VERSION 5.7 ;
  NOWIREEXTENSIONATPIN ON ;
  DIVIDERCHAR "/" ;
  BUSBITCHARS "[]" ;
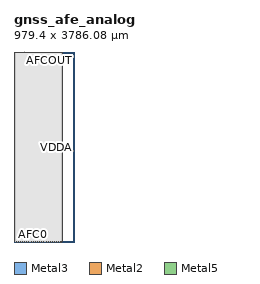
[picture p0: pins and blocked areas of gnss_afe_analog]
MACRO gnss_afe_analog
  CLASS BLOCK ;
  FOREIGN gnss_afe_analog ;
  ORIGIN 0.000 0.000 ;
  SIZE 979.400 BY 3786.080 ;
  PIN VSS
    DIRECTION INOUT ;
    USE GROUND ;
    PORT
      LAYER Metal3 ;
        RECT 6.000 6.000 9.000 3780.080 ;
    END
    PORT
      LAYER Metal2 ;
        RECT 6.500 3779.980 9.390 3786.080 ;
    END
    PORT
      LAYER Metal2 ;
        RECT 10.990 3779.980 21.240 3786.080 ;
    END
    PORT
      LAYER Metal2 ;
        RECT 24.140 3779.980 33.640 3786.080 ;
    END
    PORT
      LAYER Metal2 ;
        RECT 111.360 3779.980 120.860 3786.080 ;
    END
    PORT
      LAYER Metal2 ;
        RECT 123.760 3779.980 134.010 3786.080 ;
    END
    PORT
      LAYER Metal2 ;
        RECT 135.610 3779.980 145.860 3786.080 ;
    END
    PORT
      LAYER Metal2 ;
        RECT 149.140 3779.980 159.390 3786.080 ;
    END
    PORT
      LAYER Metal2 ;
        RECT 160.990 3779.980 171.240 3786.080 ;
    END
    PORT
      LAYER Metal2 ;
        RECT 174.140 3779.980 183.640 3786.080 ;
    END
    PORT
      LAYER Metal2 ;
        RECT 261.360 3779.980 270.860 3786.080 ;
    END
    PORT
      LAYER Metal2 ;
        RECT 273.760 3779.980 284.010 3786.080 ;
    END
    PORT
      LAYER Metal2 ;
        RECT 285.610 3779.980 295.860 3786.080 ;
    END
    PORT
      LAYER Metal2 ;
        RECT 299.140 3779.980 309.390 3786.080 ;
    END
    PORT
      LAYER Metal2 ;
        RECT 310.990 3779.980 321.240 3786.080 ;
    END
    PORT
      LAYER Metal2 ;
        RECT 324.140 3779.980 333.640 3786.080 ;
    END
    PORT
      LAYER Metal2 ;
        RECT 421.360 3779.980 430.860 3786.080 ;
    END
    PORT
      LAYER Metal2 ;
        RECT 433.760 3779.980 444.010 3786.080 ;
    END
    PORT
      LAYER Metal2 ;
        RECT 445.610 3779.980 455.860 3786.080 ;
    END
    PORT
      LAYER Metal2 ;
        RECT 459.140 3779.980 469.390 3786.080 ;
    END
    PORT
      LAYER Metal2 ;
        RECT 470.990 3779.980 481.240 3786.080 ;
    END
    PORT
      LAYER Metal2 ;
        RECT 484.140 3779.980 493.640 3786.080 ;
    END
    PORT
      LAYER Metal5 ;
        RECT 6.000 3777.080 973.400 3780.080 ;
    END
  END VSS
  PIN VDDA
    DIRECTION INOUT ;
    USE POWER ;
    PORT
      LAYER Metal3 ;
        RECT 970.400 6.000 973.400 3780.080 ;
    END
    PORT
      LAYER Metal2 ;
        RECT 36.360 3770.980 45.860 3786.080 ;
    END
    PORT
      LAYER Metal2 ;
        RECT 48.760 3770.980 59.010 3786.080 ;
    END
    PORT
      LAYER Metal2 ;
        RECT 60.610 3770.980 70.860 3786.080 ;
    END
    PORT
      LAYER Metal2 ;
        RECT 74.140 3770.980 84.390 3786.080 ;
    END
    PORT
      LAYER Metal2 ;
        RECT 85.990 3770.980 96.240 3786.080 ;
    END
    PORT
      LAYER Metal2 ;
        RECT 99.140 3770.980 108.640 3786.080 ;
    END
    PORT
      LAYER Metal5 ;
        RECT 6.000 3768.080 45.500 3771.080 ;
    END
    PORT
      LAYER Metal5 ;
        RECT 56.500 3768.080 85.500 3771.080 ;
    END
    PORT
      LAYER Metal5 ;
        RECT 96.500 3768.080 125.500 3771.080 ;
    END
    PORT
      LAYER Metal5 ;
        RECT 136.500 3768.080 165.500 3771.080 ;
    END
    PORT
      LAYER Metal5 ;
        RECT 176.500 3768.080 205.500 3771.080 ;
    END
    PORT
      LAYER Metal5 ;
        RECT 216.500 3768.080 245.500 3771.080 ;
    END
    PORT
      LAYER Metal5 ;
        RECT 256.500 3768.080 285.500 3771.080 ;
    END
    PORT
      LAYER Metal5 ;
        RECT 296.500 3768.080 325.500 3771.080 ;
    END
    PORT
      LAYER Metal5 ;
        RECT 336.500 3768.080 365.500 3771.080 ;
    END
    PORT
      LAYER Metal5 ;
        RECT 376.500 3768.080 405.500 3771.080 ;
    END
    PORT
      LAYER Metal5 ;
        RECT 416.500 3768.080 445.500 3771.080 ;
    END
    PORT
      LAYER Metal5 ;
        RECT 456.500 3768.080 485.500 3771.080 ;
    END
    PORT
      LAYER Metal5 ;
        RECT 496.500 3768.080 525.500 3771.080 ;
    END
    PORT
      LAYER Metal5 ;
        RECT 536.500 3768.080 565.500 3771.080 ;
    END
    PORT
      LAYER Metal5 ;
        RECT 576.500 3768.080 585.500 3771.080 ;
    END
    PORT
      LAYER Metal5 ;
        RECT 596.500 3768.080 605.500 3771.080 ;
    END
    PORT
      LAYER Metal5 ;
        RECT 616.500 3768.080 645.500 3771.080 ;
    END
    PORT
      LAYER Metal5 ;
        RECT 656.500 3768.080 665.500 3771.080 ;
    END
    PORT
      LAYER Metal5 ;
        RECT 676.500 3768.080 685.500 3771.080 ;
    END
    PORT
      LAYER Metal5 ;
        RECT 696.500 3768.080 725.500 3771.080 ;
    END
    PORT
      LAYER Metal5 ;
        RECT 736.500 3768.080 745.500 3771.080 ;
    END
    PORT
      LAYER Metal5 ;
        RECT 756.500 3768.080 765.500 3771.080 ;
    END
    PORT
      LAYER Metal5 ;
        RECT 776.500 3768.080 805.500 3771.080 ;
    END
    PORT
      LAYER Metal5 ;
        RECT 816.500 3768.080 825.500 3771.080 ;
    END
    PORT
      LAYER Metal5 ;
        RECT 836.500 3768.080 845.500 3771.080 ;
    END
    PORT
      LAYER Metal5 ;
        RECT 856.500 3768.080 885.500 3771.080 ;
    END
    PORT
      LAYER Metal5 ;
        RECT 896.500 3768.080 905.500 3771.080 ;
    END
    PORT
      LAYER Metal5 ;
        RECT 916.500 3768.080 925.500 3771.080 ;
    END
    PORT
      LAYER Metal5 ;
        RECT 936.500 3768.080 973.400 3771.080 ;
    END
  END VDDA
  PIN RFIN
    DIRECTION INOUT ;
    USE SIGNAL ;
    ANTENNADIFFAREA 33.599998 ;
    PORT
      LAYER Metal2 ;
        RECT 200.340 3784.040 244.660 3786.080 ;
    END
  END RFIN
  PIN VDDV
    DIRECTION INOUT ;
    USE POWER ;
    PORT
      LAYER Metal2 ;
        RECT 346.360 3775.480 355.860 3786.080 ;
    END
    PORT
      LAYER Metal2 ;
        RECT 358.760 3775.480 369.010 3786.080 ;
    END
    PORT
      LAYER Metal2 ;
        RECT 370.610 3775.480 380.860 3786.080 ;
    END
    PORT
      LAYER Metal2 ;
        RECT 384.140 3775.480 394.390 3786.080 ;
    END
    PORT
      LAYER Metal2 ;
        RECT 395.990 3775.480 406.240 3786.080 ;
    END
    PORT
      LAYER Metal2 ;
        RECT 409.140 3775.480 418.640 3786.080 ;
    END
    PORT
      LAYER Metal5 ;
        RECT 6.000 3772.580 45.500 3775.580 ;
    END
    PORT
      LAYER Metal5 ;
        RECT 56.500 3772.580 85.500 3775.580 ;
    END
    PORT
      LAYER Metal5 ;
        RECT 96.500 3772.580 125.500 3775.580 ;
    END
    PORT
      LAYER Metal5 ;
        RECT 136.500 3772.580 165.500 3775.580 ;
    END
    PORT
      LAYER Metal5 ;
        RECT 176.500 3772.580 205.500 3775.580 ;
    END
    PORT
      LAYER Metal5 ;
        RECT 216.500 3772.580 245.500 3775.580 ;
    END
    PORT
      LAYER Metal5 ;
        RECT 256.500 3772.580 285.500 3775.580 ;
    END
    PORT
      LAYER Metal5 ;
        RECT 296.500 3772.580 325.500 3775.580 ;
    END
    PORT
      LAYER Metal5 ;
        RECT 336.500 3772.580 365.500 3775.580 ;
    END
    PORT
      LAYER Metal5 ;
        RECT 376.500 3772.580 405.500 3775.580 ;
    END
    PORT
      LAYER Metal5 ;
        RECT 416.500 3772.580 445.500 3775.580 ;
    END
    PORT
      LAYER Metal5 ;
        RECT 456.500 3772.580 485.500 3775.580 ;
    END
    PORT
      LAYER Metal5 ;
        RECT 496.500 3772.580 525.500 3775.580 ;
    END
    PORT
      LAYER Metal5 ;
        RECT 536.500 3772.580 565.500 3775.580 ;
    END
    PORT
      LAYER Metal5 ;
        RECT 576.500 3772.580 605.500 3775.580 ;
    END
    PORT
      LAYER Metal5 ;
        RECT 616.500 3772.580 645.500 3775.580 ;
    END
    PORT
      LAYER Metal5 ;
        RECT 656.500 3772.580 685.500 3775.580 ;
    END
    PORT
      LAYER Metal5 ;
        RECT 696.500 3772.580 725.500 3775.580 ;
    END
    PORT
      LAYER Metal5 ;
        RECT 736.500 3772.580 765.500 3775.580 ;
    END
    PORT
      LAYER Metal5 ;
        RECT 776.500 3772.580 805.500 3775.580 ;
    END
    PORT
      LAYER Metal5 ;
        RECT 816.500 3772.580 845.500 3775.580 ;
    END
    PORT
      LAYER Metal5 ;
        RECT 856.500 3772.580 885.500 3775.580 ;
    END
    PORT
      LAYER Metal5 ;
        RECT 896.500 3772.580 925.500 3775.580 ;
    END
    PORT
      LAYER Metal5 ;
        RECT 936.500 3772.580 973.400 3775.580 ;
    END
  END VDDV
  PIN VCTRL
    DIRECTION INOUT ;
    USE SIGNAL ;
    PORT
      LAYER Metal2 ;
        RECT 794.500 3784.040 804.500 3786.080 ;
    END
  END VCTRL
  PIN AFCOUT
    DIRECTION INOUT ;
    USE SIGNAL ;
    PORT
      LAYER Metal2 ;
        RECT 903.500 3784.040 913.500 3786.080 ;
    END
  END AFCOUT
  PIN REFIN
    DIRECTION INOUT ;
    USE SIGNAL ;
    PORT
      LAYER Metal2 ;
        RECT 925.000 3784.040 935.000 3786.080 ;
    END
  END REFIN
  PIN IG1A
    DIRECTION INOUT ;
    USE SIGNAL ;
    ANTENNAGATEAREA 11.200000 ;
    PORT
      LAYER Metal3 ;
        RECT 41.200 -0.100 42.200 0.900 ;
    END
  END IG1A
  PIN IG1B
    DIRECTION INOUT ;
    USE SIGNAL ;
    ANTENNAGATEAREA 22.400000 ;
    PORT
      LAYER Metal3 ;
        RECT 83.900 -0.100 84.900 0.900 ;
    END
  END IG1B
  PIN IG2A
    DIRECTION INOUT ;
    USE SIGNAL ;
    ANTENNAGATEAREA 11.200000 ;
    PORT
      LAYER Metal3 ;
        RECT 126.600 -0.100 127.600 0.900 ;
    END
  END IG2A
  PIN IG2B
    DIRECTION INOUT ;
    USE SIGNAL ;
    ANTENNAGATEAREA 22.400000 ;
    PORT
      LAYER Metal3 ;
        RECT 169.300 -0.100 170.300 0.900 ;
    END
  END IG2B
  PIN IG3A
    DIRECTION INOUT ;
    USE SIGNAL ;
    ANTENNAGATEAREA 11.200000 ;
    PORT
      LAYER Metal3 ;
        RECT 212.000 -0.100 213.000 0.900 ;
    END
  END IG3A
  PIN IG3B
    DIRECTION INOUT ;
    USE SIGNAL ;
    ANTENNAGATEAREA 22.400000 ;
    PORT
      LAYER Metal3 ;
        RECT 254.700 -0.100 255.700 0.900 ;
    END
  END IG3B
  PIN B0
    DIRECTION INOUT ;
    USE SIGNAL ;
    ANTENNAGATEAREA 0.840000 ;
    PORT
      LAYER Metal3 ;
        RECT 297.400 -0.100 298.400 0.900 ;
    END
  END B0
  PIN B1
    DIRECTION INOUT ;
    USE SIGNAL ;
    ANTENNAGATEAREA 0.840000 ;
    PORT
      LAYER Metal3 ;
        RECT 339.400 -0.100 340.400 0.900 ;
    END
  END B1
  PIN AFC0
    DIRECTION INOUT ;
    USE SIGNAL ;
    ANTENNAGATEAREA 0.840000 ;
    PORT
      LAYER Metal3 ;
        RECT 382.100 -0.100 383.100 0.900 ;
    END
  END AFC0
  PIN AFC1
    DIRECTION INOUT ;
    USE SIGNAL ;
    ANTENNAGATEAREA 0.840000 ;
    PORT
      LAYER Metal3 ;
        RECT 424.800 -0.100 425.800 0.900 ;
    END
  END AFC1
  PIN AFC2
    DIRECTION INOUT ;
    USE SIGNAL ;
    ANTENNAGATEAREA 0.840000 ;
    PORT
      LAYER Metal3 ;
        RECT 467.500 -0.100 468.500 0.900 ;
    END
  END AFC2
  PIN AFC3
    DIRECTION INOUT ;
    USE SIGNAL ;
    ANTENNAGATEAREA 0.840000 ;
    PORT
      LAYER Metal3 ;
        RECT 510.200 -0.100 511.200 0.900 ;
    END
  END AFC3
  PIN AFC4
    DIRECTION INOUT ;
    USE SIGNAL ;
    ANTENNAGATEAREA 0.840000 ;
    PORT
      LAYER Metal3 ;
        RECT 552.900 -0.100 553.900 0.900 ;
    END
  END AFC4
  PIN AFC5
    DIRECTION INOUT ;
    USE SIGNAL ;
    ANTENNAGATEAREA 0.840000 ;
    PORT
      LAYER Metal3 ;
        RECT 595.600 -0.100 596.600 0.900 ;
    END
  END AFC5
  PIN AFC6
    DIRECTION INOUT ;
    USE SIGNAL ;
    ANTENNAGATEAREA 0.840000 ;
    PORT
      LAYER Metal3 ;
        RECT 638.300 -0.100 639.300 0.900 ;
    END
  END AFC6
  PIN AFC7
    DIRECTION INOUT ;
    USE SIGNAL ;
    ANTENNAGATEAREA 0.840000 ;
    PORT
      LAYER Metal3 ;
        RECT 680.300 -0.100 681.300 0.900 ;
    END
  END AFC7
  PIN ICP2
    DIRECTION INOUT ;
    USE SIGNAL ;
    ANTENNAGATEAREA 1.960000 ;
    PORT
      LAYER Metal3 ;
        RECT 723.000 -0.100 724.000 0.900 ;
    END
  END ICP2
  PIN I_SIGN
    DIRECTION INOUT ;
    USE SIGNAL ;
    ANTENNAGATEAREA 1.400000 ;
    ANTENNADIFFAREA 2.670000 ;
    PORT
      LAYER Metal3 ;
        RECT 765.700 -0.100 766.700 0.900 ;
    END
  END I_SIGN
  PIN I_MAG
    DIRECTION INOUT ;
    USE SIGNAL ;
    ANTENNADIFFAREA 2.670000 ;
    PORT
      LAYER Metal3 ;
        RECT 808.400 -0.100 809.400 0.900 ;
    END
  END I_MAG
  PIN Q_SIGN
    DIRECTION INOUT ;
    USE SIGNAL ;
    ANTENNAGATEAREA 1.400000 ;
    ANTENNADIFFAREA 2.670000 ;
    PORT
      LAYER Metal3 ;
        RECT 851.100 -0.100 852.100 0.900 ;
    END
  END Q_SIGN
  PIN Q_MAG
    DIRECTION INOUT ;
    USE SIGNAL ;
    ANTENNADIFFAREA 2.670000 ;
    PORT
      LAYER Metal3 ;
        RECT 893.800 -0.100 894.800 0.900 ;
    END
  END Q_MAG
  PIN CLKOUT
    DIRECTION INOUT ;
    USE SIGNAL ;
    ANTENNADIFFAREA 4.770000 ;
    PORT
      LAYER Metal3 ;
        RECT 936.500 -0.100 937.500 0.900 ;
    END
  END CLKOUT
  OBS
      LAYER Nwell ;
        RECT 33.760 16.260 946.360 3761.380 ;
      LAYER Metal1 ;
        RECT 33.945 16.445 946.175 3761.195 ;
      LAYER Metal2 ;
        RECT 9.690 3779.680 10.690 3784.090 ;
        RECT 21.540 3779.680 23.840 3784.090 ;
        RECT 33.940 3779.680 36.060 3784.090 ;
        RECT 6.500 3770.680 36.060 3779.680 ;
        RECT 46.160 3770.680 48.460 3784.090 ;
        RECT 59.310 3770.680 60.310 3784.090 ;
        RECT 71.160 3770.680 73.840 3784.090 ;
        RECT 84.690 3770.680 85.690 3784.090 ;
        RECT 96.540 3770.680 98.840 3784.090 ;
        RECT 108.940 3779.680 111.060 3784.090 ;
        RECT 121.160 3779.680 123.460 3784.090 ;
        RECT 134.310 3779.680 135.310 3784.090 ;
        RECT 146.160 3779.680 148.840 3784.090 ;
        RECT 159.690 3779.680 160.690 3784.090 ;
        RECT 171.540 3779.680 173.840 3784.090 ;
        RECT 183.940 3783.740 200.040 3784.090 ;
        RECT 244.960 3783.740 261.060 3784.090 ;
        RECT 183.940 3779.680 261.060 3783.740 ;
        RECT 271.160 3779.680 273.460 3784.090 ;
        RECT 284.310 3779.680 285.310 3784.090 ;
        RECT 296.160 3779.680 298.840 3784.090 ;
        RECT 309.690 3779.680 310.690 3784.090 ;
        RECT 321.540 3779.680 323.840 3784.090 ;
        RECT 333.940 3779.680 346.060 3784.090 ;
        RECT 108.940 3775.180 346.060 3779.680 ;
        RECT 356.160 3775.180 358.460 3784.090 ;
        RECT 369.310 3775.180 370.310 3784.090 ;
        RECT 381.160 3775.180 383.840 3784.090 ;
        RECT 394.690 3775.180 395.690 3784.090 ;
        RECT 406.540 3775.180 408.840 3784.090 ;
        RECT 418.940 3779.680 421.060 3784.090 ;
        RECT 431.160 3779.680 433.460 3784.090 ;
        RECT 444.310 3779.680 445.310 3784.090 ;
        RECT 456.160 3779.680 458.840 3784.090 ;
        RECT 469.690 3779.680 470.690 3784.090 ;
        RECT 481.540 3779.680 483.840 3784.090 ;
        RECT 493.940 3783.740 794.200 3784.090 ;
        RECT 804.800 3783.740 903.200 3784.090 ;
        RECT 913.800 3783.740 924.700 3784.090 ;
        RECT 935.300 3783.740 956.790 3784.090 ;
        RECT 493.940 3779.680 956.790 3783.740 ;
        RECT 418.940 3775.180 956.790 3779.680 ;
        RECT 108.940 3770.680 956.790 3775.180 ;
        RECT 6.500 1.610 956.790 3770.680 ;
      LAYER Metal3 ;
        RECT 200.450 3786.080 202.850 3786.150 ;
        RECT 9.000 3780.380 956.790 3786.080 ;
        RECT 9.300 5.700 956.790 3780.380 ;
        RECT 9.000 1.200 956.790 5.700 ;
        RECT 9.000 0.900 40.900 1.200 ;
        RECT 42.500 0.900 83.600 1.200 ;
        RECT 85.200 0.900 126.300 1.200 ;
        RECT 127.900 0.900 169.000 1.200 ;
        RECT 170.600 0.900 211.700 1.200 ;
        RECT 213.300 0.900 254.400 1.200 ;
        RECT 256.000 0.900 297.100 1.200 ;
        RECT 298.700 0.900 339.100 1.200 ;
        RECT 340.700 0.900 381.800 1.200 ;
        RECT 383.400 0.900 424.500 1.200 ;
        RECT 426.100 0.900 467.200 1.200 ;
        RECT 468.800 0.900 509.900 1.200 ;
        RECT 511.500 0.900 552.600 1.200 ;
        RECT 554.200 0.900 595.300 1.200 ;
        RECT 596.900 0.900 638.000 1.200 ;
        RECT 639.600 0.900 680.000 1.200 ;
        RECT 681.600 0.900 722.700 1.200 ;
        RECT 724.300 0.900 765.400 1.200 ;
        RECT 767.000 0.900 808.100 1.200 ;
        RECT 809.700 0.900 850.800 1.200 ;
        RECT 852.400 0.900 893.500 1.200 ;
        RECT 895.100 0.900 936.200 1.200 ;
        RECT 937.800 0.900 956.790 1.200 ;
      LAYER Metal4 ;
        RECT 6.000 1.610 973.400 3784.090 ;
      LAYER Metal5 ;
        RECT 26.000 3776.180 956.000 3776.480 ;
        RECT 46.100 3771.980 55.900 3776.180 ;
        RECT 86.100 3771.980 95.900 3776.180 ;
        RECT 126.100 3771.980 135.900 3776.180 ;
        RECT 166.100 3771.980 175.900 3776.180 ;
        RECT 206.100 3771.980 215.900 3776.180 ;
        RECT 246.100 3771.980 255.900 3776.180 ;
        RECT 286.100 3771.980 295.900 3776.180 ;
        RECT 326.100 3771.980 335.900 3776.180 ;
        RECT 366.100 3771.980 375.900 3776.180 ;
        RECT 406.100 3771.980 415.900 3776.180 ;
        RECT 446.100 3771.980 455.900 3776.180 ;
        RECT 486.100 3771.980 495.900 3776.180 ;
        RECT 526.100 3771.980 535.900 3776.180 ;
        RECT 566.100 3771.980 575.900 3776.180 ;
        RECT 606.100 3771.980 615.900 3776.180 ;
        RECT 646.100 3771.980 655.900 3776.180 ;
        RECT 686.100 3771.980 695.900 3776.180 ;
        RECT 726.100 3771.980 735.900 3776.180 ;
        RECT 766.100 3771.980 775.900 3776.180 ;
        RECT 806.100 3771.980 815.900 3776.180 ;
        RECT 846.100 3771.980 855.900 3776.180 ;
        RECT 886.100 3771.980 895.900 3776.180 ;
        RECT 926.100 3771.980 935.900 3776.180 ;
        RECT 26.000 3771.680 956.000 3771.980 ;
        RECT 46.100 3767.480 55.900 3771.680 ;
        RECT 86.100 3767.480 95.900 3771.680 ;
        RECT 126.100 3767.480 135.900 3771.680 ;
        RECT 166.100 3767.480 175.900 3771.680 ;
        RECT 206.100 3767.480 215.900 3771.680 ;
        RECT 246.100 3767.480 255.900 3771.680 ;
        RECT 286.100 3767.480 295.900 3771.680 ;
        RECT 326.100 3767.480 335.900 3771.680 ;
        RECT 366.100 3767.480 375.900 3771.680 ;
        RECT 406.100 3767.480 415.900 3771.680 ;
        RECT 446.100 3767.480 455.900 3771.680 ;
        RECT 486.100 3767.480 495.900 3771.680 ;
        RECT 526.100 3767.480 535.900 3771.680 ;
        RECT 566.100 3767.480 575.900 3771.680 ;
        RECT 586.100 3767.480 595.900 3771.680 ;
        RECT 606.100 3767.480 615.900 3771.680 ;
        RECT 646.100 3767.480 655.900 3771.680 ;
        RECT 666.100 3767.480 675.900 3771.680 ;
        RECT 686.100 3767.480 695.900 3771.680 ;
        RECT 726.100 3767.480 735.900 3771.680 ;
        RECT 746.100 3767.480 755.900 3771.680 ;
        RECT 766.100 3767.480 775.900 3771.680 ;
        RECT 806.100 3767.480 815.900 3771.680 ;
        RECT 826.100 3767.480 835.900 3771.680 ;
        RECT 846.100 3767.480 855.900 3771.680 ;
        RECT 886.100 3767.480 895.900 3771.680 ;
        RECT 906.100 3767.480 915.900 3771.680 ;
        RECT 926.100 3767.480 935.900 3771.680 ;
        RECT 26.000 6.000 956.000 3767.480 ;
  END
END gnss_afe_analog
END LIBRARY

